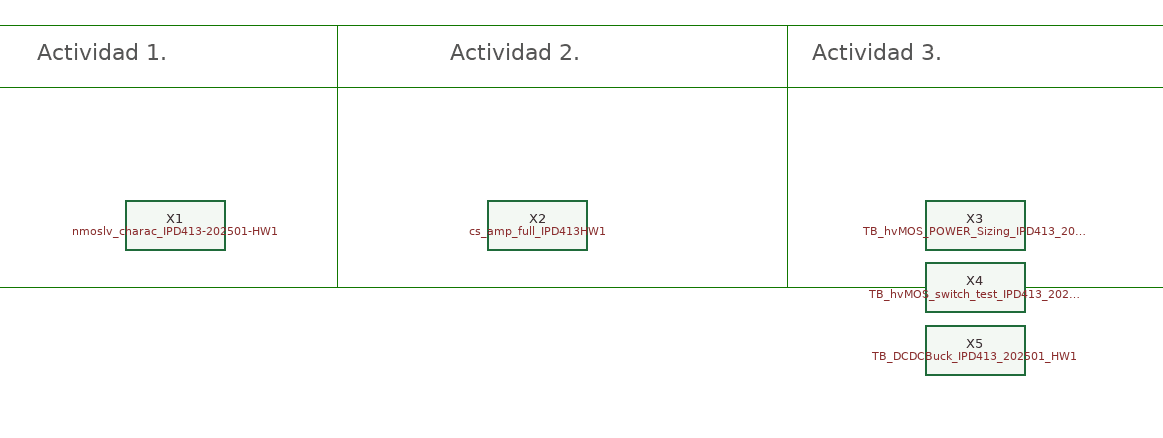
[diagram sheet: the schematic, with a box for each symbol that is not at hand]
v {xschem version=3.4.5 file_version=1.2
}
G {}
K {}
V {}
S {}
E {}
L 4 -4280 -810 -4280 -620 {}
L 4 -4280 -620 -4280 -600 {}
L 4 -3990 -810 -3990 -620 {}
L 4 -3990 -620 -3990 -600 {}
L 4 -3630 -810 -3630 -620 {}
L 4 -3630 -620 -3630 -600 {}
L 4 -3280 -810 -3280 -620 {}
L 4 -3280 -620 -3280 -600 {}
L 4 -4280 -810 -3280 -810 {}
L 4 -4280 -600 -3280 -600 {}
L 4 -4280 -760 -3280 -760 {}
T {Actividad 1.} -4230 -800 0 0 0.6 0.6 {}
T {Actividad 2.} -3900 -800 0 0 0.6 0.6 {}
T {Actividad 3.} -3610 -800 0 0 0.6 0.6 {}
C {title.sym} -4150 -530 0 0 {name=l1 author="Prof: Jorge Marín , Ayudante: Andrés Martínez"}
C {../Tarea_1/nmoslv_charac_IPD413-202501-HW1.sym} -4120 -650 0 0 {name=X1}
C {../Tarea_1/TB_hvMOS_POWER_Sizing_IPD413_202501_HW1.sym} -3480 -650 0 0 {name=X3}
C {../Tarea_1/TB_hvMOS_switch_test_IPD413_202501_HW1.sym} -3480 -600 0 0 {name=X4}
C {../Tarea_1/TB_DCDCBuck_IPD413_202501_HW1.sym} -3480 -550 0 0 {name=X5}
C {/home/designer/shared/IPD413_202501/xschem/Tareas/Tarea_1/cs_amp_full_IPD413HW1.sym} -3830 -650 0 0 {name=X2}
